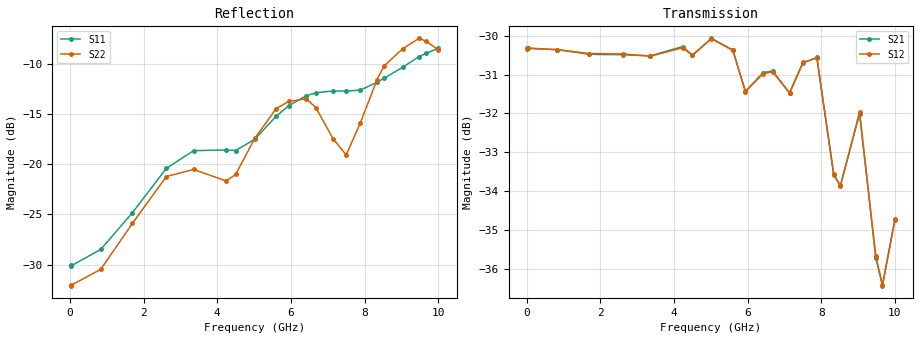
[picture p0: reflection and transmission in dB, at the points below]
! Integrated Device Technology
! Corporate Headquarters
! 6024 Silver Creek Valley Road
! San Jose, CA 95138  USA
! Phone:  1-408-284-8200
! Toll Free:  1-800-223-1366
! Webpage:  http://www.idt.com/
! Timing and RF Division
! 515 Groton Road, Suite 102
! Westford, MA 01886-6024
! Device:  F1958
! Description: 7-bit 0.25 dB Digital Step Attenuator
! Frequency:  0.001 -  6.000 GHz
! Package:  4x4 mm Thin QFN Plastic Package: 24 pin
! Ports:  2 RF, 12 DC
!  Pin  1  = D0
!  Pin  2  = VDD
!  Pin  3  = VMODE
!  Pin  4  = GND
!  Pin  5  = RF1  =  Port 1
!  Pin  6  = GND
!  Pin  7  = GND
!  Pin  8  = GND
!  Pin  9  = GND
!  Pin 10  = GND
!  Pin 11  = GND
!  Pin 12  = GND
!  Pin 13  = GND
!  Pin 14  = RF2  =  Port 2
!  Pin 15  = GND
!  Pin 16  = LE
!  Pin 17  = CLK
!  Pin 18  = DATA
!  Pin 19  = D6
!  Pin 20  = D5
!  Pin 21  = D4
!  Pin 22  = D3
!  Pin 23  = D2
!  Pin 24  = D1
! State:  118
! Atten State:  29.50 dB
! Voltage:  +3.30 Volts
! Current:  0.258 mA
! Data:  The device was measured on a F1958 evaluation board which has
!  individual transmission lines to the RF pins.  Data was collected
!  using a calibrated network analyzer.  The evaluation board was
!  de-embedded using Automatic Fixture Removal (AFR).
!  The reference plane is the edge of the package pin.
! Misc:
!  Action Tracker AT0419
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# GHz S dB R 50
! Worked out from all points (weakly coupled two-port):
!   500 points, 20 MHz to 10 GHz, reference 50 ohm
!   highest |S21| = -30.07 dB at 5.02 GHz (marker M1); lowest = -36.4 dB at 9.66 GHz (marker M2)
!   lowest |S11| = -30.1 dB at 40 MHz (marker M3), VSWR 1.06, Z = 47 - j0.044 ohm
!   |S11| at or under -10 dB: start of sweep to 9.148 GHz
!   |S22| runs from -32.3 to -7.5 dB; largest |S21 - S12| = 0.00031
!   S11 on the Smith chart (normalised r, x): 20 MHz: 0.94, -0.00; 6.42 GHz: 0.67, +0.17; 10 GHz: 0.67, +0.58
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0.02  -30.08 -178.9  -30.35 -0.2  -30.33 -0.1  -32.09 -178.9
0.04  -30.11 -179.1  -30.33 -0.3  -30.32 -0.3  -32.04 -178.4
0.84  -28.48 170.7  -30.36 -9.5  -30.36 -9.5  -30.46 172.1
1.7  -24.82 170.6  -30.48 -18.8  -30.46 -18.9  -25.88 171.0
2.62  -20.42 176.7  -30.49 -28.9  -30.47 -28.9  -21.23 -179.7
3.36  -18.66 -175.8  -30.52 -37.5  -30.53 -37.7  -20.53 -169.3
4.24  -18.59 -179.1  -30.28 -47.2  -30.31 -47.4  -21.67 168.9
4.5  -18.65 175.0  -30.50 -50.9  -30.51 -50.9  -21.03 151.3
5.02  -17.52 160.7  -30.07 -57.3  -30.08 -57.3  -17.43 138.2
5.6  -15.23 150.7  -30.37 -66.0  -30.38 -65.9  -14.48 140.2
5.94  -14.20 148.3  -31.43 -69.8  -31.44 -69.9  -13.76 148.7
6.42  -13.19 147.7  -30.95 -75.3  -30.98 -75.2  -13.50 157.3
6.68  -12.90 146.8  -30.91 -77.9  -30.93 -77.8  -14.39 157.9
7.14  -12.72 143.0  -31.47 -83.4  -31.48 -83.3  -17.45 152.4
7.5  -12.73 138.5  -30.71 -87.0  -30.69 -86.8  -19.09 120.4
7.88  -12.64 130.3  -30.56 -101.4  -30.57 -101.4  -15.95 88.4
8.34  -11.86 119.2  -33.59 -108.3  -33.57 -108.5  -11.59 84.2
8.52  -11.48 115.8  -33.85 -101.0  -33.87 -101.1  -10.27 87.6
9.04  -10.35 107.2  -32.01 -110.2  -31.96 -110.1  -8.50 97.7
9.48  -9.31 102.1  -35.71 -115.6  -35.67 -115.4  -7.49 107.9
9.66  -8.99 101.0  -36.43 -105.5  -36.40 -105.2  -7.76 110.5
10  -8.47 100.1  -34.72 -92.2  -34.75 -92.1  -8.62 114.3
